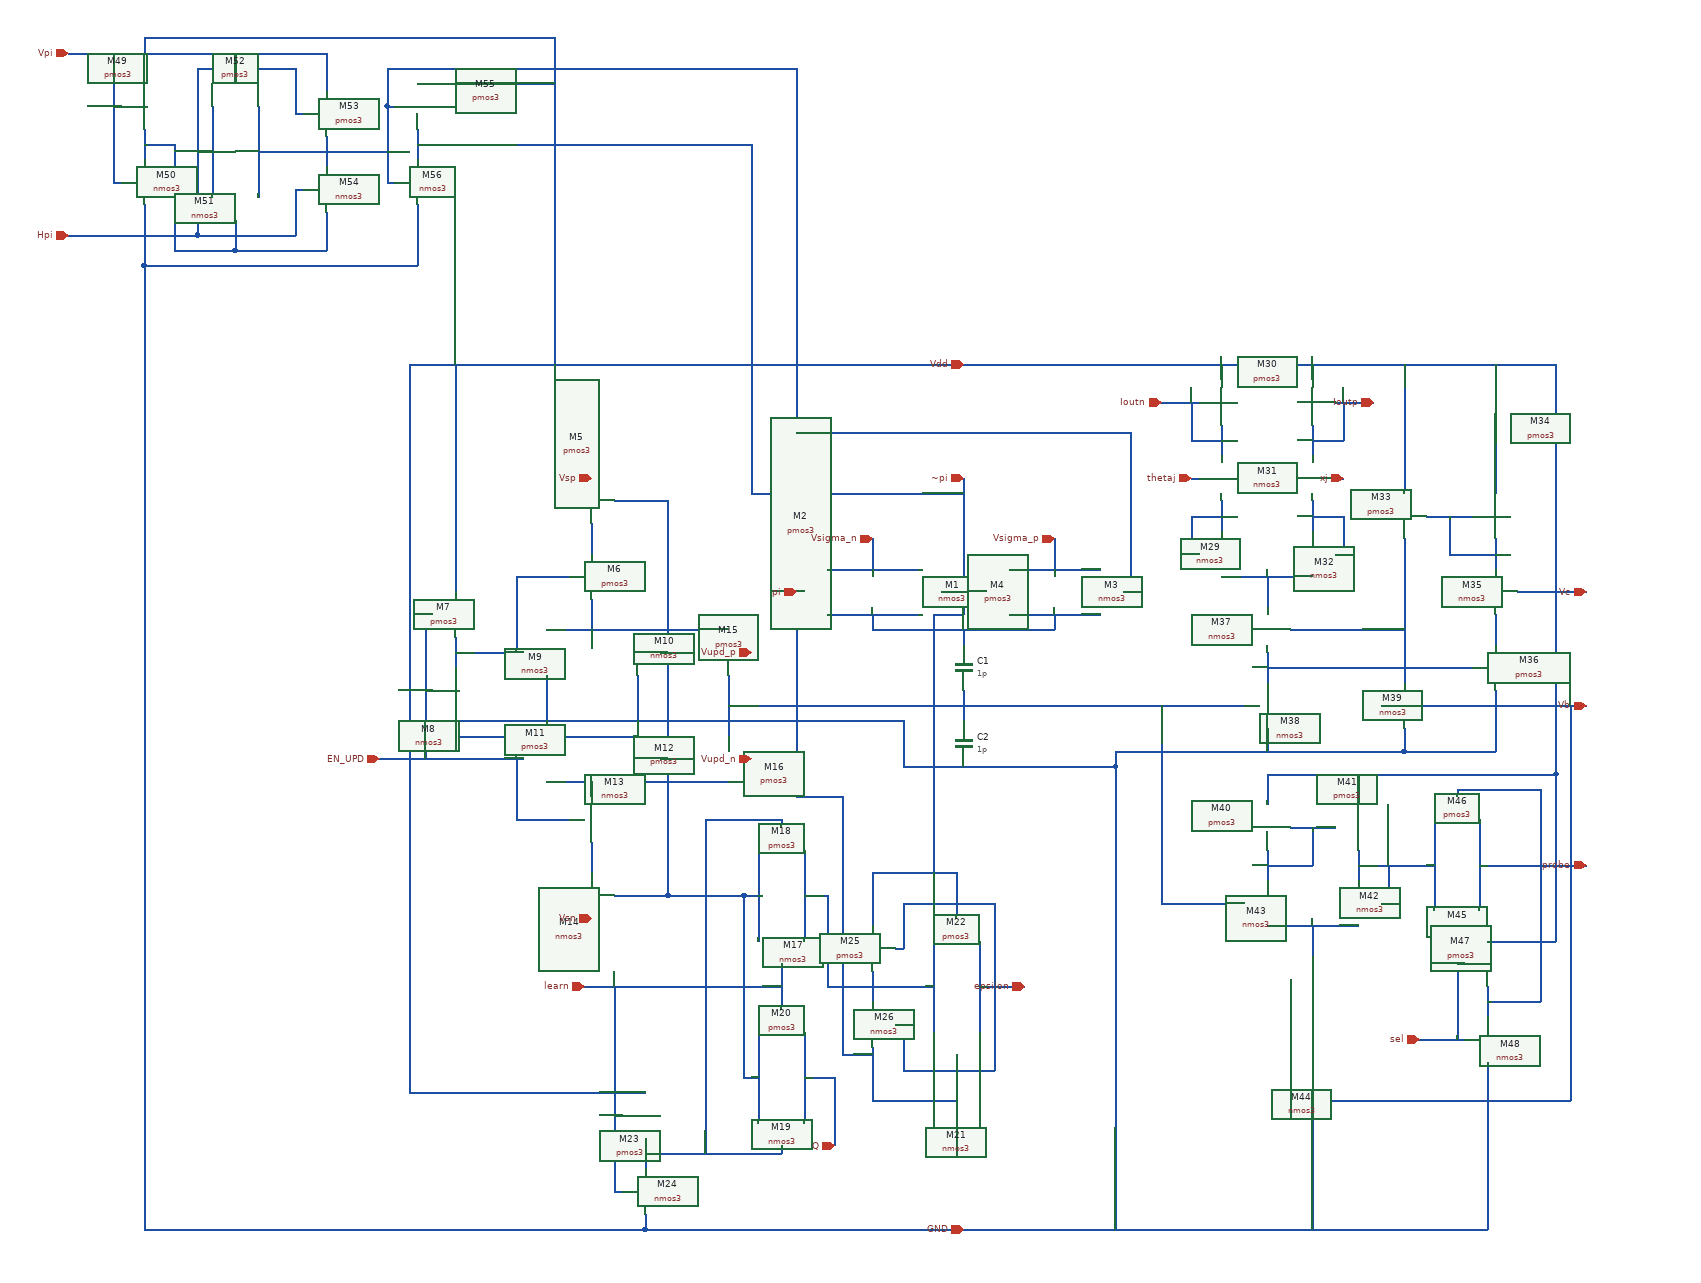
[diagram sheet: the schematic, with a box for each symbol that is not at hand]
v {xschem version=3.4.5 file_version=1.2
}
G {}
K {}
V {}
S {}
E {}
N -180 -80 -60 -80 {
lab=Vsigma_n}
N 60 -80 180 -80 {
lab=Vsigma_p}
N -180 -20 -60 -20 {
lab=#net1}
N 60 -20 180 -20 {
lab=#net1}
N -30 -50 30 -50 {
lab=~pi}
N 0 -200 0 -50 {
lab=~pi}
N -220 -50 -210 -50 {
lab=pi}
N 210 -50 220 -50 {
lab=pi}
N -120 -20 -120 0 {
lab=#net1}
N -120 0 120 0 {
lab=#net1}
N 120 -20 120 0 {
lab=#net1}
N 0 0 0 20 {
lab=#net1}
N -550 0 -430 0 {
lab=#net2}
N -490 -40 -490 0 {
lab=#net2}
N -490 -140 -490 -100 {
lab=#net3}
N -590 -70 -520 -70 {
lab=#net4}
N -590 -70 -590 30 {
lab=#net4}
N -670 10 -670 50 {
lab=#net4}
N -670 30 -580 30 {
lab=#net4}
N -490 280 -490 320 {
lab=#net5}
N -550 200 -430 200 {
lab=#net6}
N -490 200 -490 220 {
lab=#net6}
N -460 350 -390 350 {
lab=#net7}
N -400 170 -390 170 {
lab=#net7}
N -400 30 -390 30 {
lab=#net7}
N -710 -20 -700 -20 {
lab=EN_UPD}
N -710 80 -700 80 {
lab=EN_UPD}
N -590 170 -590 250 {
lab=EN_UPD}
N -590 250 -520 250 {
lab=EN_UPD}
N -460 -170 -390 -170 {
lab=#net7}
N -390 -170 -390 350 {
lab=#net7}
N -710 -20 -710 170 {
lab=EN_UPD}
N -310 60 -310 140 {
lab=#net8}
N -430 0 -310 0 {
lab=#net2}
N -430 200 -310 200 {
lab=#net6}
N -310 100 -0 100 {
lab=#net8}
N -0 80 0 120 {
lab=#net8}
N -210 290 -210 410 {
lab=#net9}
N -210 530 -210 650 {
lab=Q}
N -270 290 -270 410 {
lab=#net7}
N -270 530 -270 650 {
lab=#net7}
N -240 440 -240 500 {
lab=learn}
N -240 250 -240 260 {
lab=#net10}
N -240 680 -240 690 {
lab=#net10}
N -290 350 -270 350 {
lab=#net7}
N -290 350 -290 590 {
lab=#net7}
N -290 590 -270 590 {
lab=#net7}
N 20 410 20 530 {
lab=epsilon}
N -40 410 -40 530 {
lab=#net9}
N -420 670 -420 710 {
lab=#net10}
N -460 640 -450 640 {
lab=learn}
N -460 740 -450 740 {
lab=learn}
N -420 690 -240 690 {
lab=#net10}
N -460 470 -460 740 {
lab=learn}
N -500 470 -240 470 {
lab=learn}
N -340 250 -240 250 {
lab=#net10}
N -340 250 -340 690 {
lab=#net10}
N -390 350 -290 350 {
lab=#net7}
N -120 450 -120 490 {
lab=#net9}
N -210 350 -180 350 {
lab=#net9}
N -180 350 -180 470 {
lab=#net9}
N -180 470 -120 470 {
lab=#net9}
N -120 470 -40 470 {
lab=#net9}
N -120 550 -120 620 {
lab=pi}
N -120 620 -10 620 {
lab=pi}
N -10 560 -10 620 {
lab=pi}
N -120 320 -120 390 {
lab=~pi}
N -120 320 -10 320 {
lab=~pi}
N -10 320 -10 380 {
lab=~pi}
N -90 520 -80 520 {
lab=epsilon}
N -80 520 -80 580 {
lab=epsilon}
N -80 580 40 580 {
lab=epsilon}
N 40 360 40 580 {
lab=epsilon}
N -80 360 40 360 {
lab=epsilon}
N -80 360 -80 420 {
lab=epsilon}
N -90 420 -80 420 {
lab=epsilon}
N 20 470 40 470 {
lab=epsilon}
N 340 -270 340 -230 {
lab=Ioutn}
N 300 -200 310 -200 {
lab=thetaj}
N 460 -270 460 -230 {
lab=Ioutp}
N 490 -200 500 -200 {
lab=xj}
N 340 -170 340 -130 {
lab=#net11}
N 460 -170 460 -130 {
lab=#net12}
N 300 -100 310 -100 {
lab=#net11}
N 300 -150 300 -100 {
lab=#net11}
N 300 -150 340 -150 {
lab=#net11}
N 460 -150 500 -150 {
lab=#net12}
N 500 -150 500 -100 {
lab=#net12}
N 490 -100 500 -100 {
lab=#net12}
N 340 -70 460 -70 {
lab=#net13}
N 300 -300 300 -250 {
lab=Ioutn}
N 300 -250 340 -250 {
lab=Ioutn}
N 460 -250 500 -250 {
lab=Ioutp}
N 500 -300 500 -250 {
lab=Ioutp}
N 260 -300 310 -300 {
lab=Ioutn}
N 490 -300 540 -300 {
lab=Ioutp}
N 400 -70 400 -30 {
lab=#net13}
N 400 30 400 70 {
lab=#net14}
N 610 -150 670 -150 {
lab=#net15}
N 640 -150 640 -100 {
lab=#net15}
N 640 -100 700 -100 {
lab=#net15}
N 700 -120 700 -80 {
lab=#net15}
N 700 -20 700 20 {
lab=#net16}
N 400 50 670 50 {
lab=#net14}
N 580 -120 580 70 {
lab=#net17}
N 430 0 580 0 {
lab=#net17}
N 430 260 490 260 {
lab=#net18}
N 520 290 520 330 {
lab=#net19}
N 460 260 460 310 {
lab=#net18}
N 400 310 460 310 {
lab=#net18}
N 400 290 400 330 {
lab=#net18}
N 400 390 520 390 {
lab=#net20}
N 460 390 460 430 {
lab=#net20}
N 680 250 680 370 {
lab=probe}
N 620 250 620 370 {
lab=#net19}
N 40 470 80 470 {
lab=epsilon}
N 690 470 690 510 {
lab=#net21}
N 650 440 660 440 {
lab=sel}
N 520 310 620 310 {
lab=#net19}
N 550 360 560 360 {
lab=#net19}
N 560 310 560 360 {
lab=#net19}
N 650 400 650 540 {
lab=sel}
N 600 540 660 540 {
lab=sel}
N 650 210 650 220 {
lab=#net21}
N 650 210 760 210 {
lab=#net21}
N 690 490 760 490 {
lab=#net21}
N 760 210 760 490 {
lab=#net21}
N 0 100 370 100 {
lab=#net8}
N 260 360 370 360 {
lab=#net8}
N 260 100 260 360 {
lab=#net8}
N 460 -350 460 -330 {
lab=Vdd}
N 340 -350 340 -330 {
lab=Vdd}
N -670 -350 -670 -50 {
lab=Vdd}
N 700 -350 700 -180 {
lab=Vdd}
N 580 -350 580 -180 {
lab=Vdd}
N -730 140 -430 140 {
lab=Vdd}
N -730 -350 -730 140 {
lab=Vdd}
N 400 190 400 230 {
lab=Vdd}
N 520 190 520 230 {
lab=Vdd}
N 400 190 780 190 {
lab=Vdd}
N 780 -350 780 190 {
lab=Vdd}
N -730 -350 780 -350 {
lab=Vdd}
N 690 410 780 410 {
lab=Vdd}
N 780 190 780 410 {
lab=Vdd}
N -730 610 -420 610 {
lab=Vdd}
N -730 140 -730 610 {
lab=Vdd}
N -420 770 -420 790 {
lab=GND}
N -420 790 690 790 {
lab=GND}
N 690 570 690 790 {
lab=GND}
N 460 490 460 790 {
lab=GND}
N -0 180 200 180 {
lab=GND}
N 200 180 200 790 {
lab=GND}
N 580 130 580 160 {
lab=GND}
N 200 160 580 160 {
lab=GND}
N 200 160 200 180 {
lab=GND}
N 400 130 400 160 {
lab=GND}
N 700 80 700 160 {
lab=GND}
N 580 160 700 160 {
lab=GND}
N -670 110 -670 120 {
lab=GND}
N -670 120 -80 120 {
lab=GND}
N -80 120 -80 180 {
lab=GND}
N -80 180 -0 180 {
lab=GND}
N -550 60 -550 120 {
lab=GND}
N -430 60 -430 120 {
lab=GND}
N 730 -50 820 -50 {
lab=Vc}
N 680 310 820 310 {
lab=probe}
N -120 -120 -120 -80 {
lab=Vsigma_n}
N 120 -120 120 -80 {
lab=Vsigma_p}
N 550 100 820 100 {
lab=Vb}
N 430 460 430 620 {
lab=Vb}
N 430 620 800 620 {
lab=Vb}
N 800 100 800 620 {
lab=Vb}
N -210 590 -170 590 {
lab=Q}
N -170 590 -170 680 {
lab=Q}
N -220 -50 -220 220 {
lab=pi}
N -220 220 -160 220 {
lab=pi}
N -160 220 -160 560 {
lab=pi}
N -160 560 -120 560 {
lab=pi}
N 0 -50 0 -20 {
lab=~pi}
N -40 -20 0 -20 {
lab=~pi}
N -40 -20 -40 320 {
lab=~pi}
N -770 170 -580 170 {
lab=EN_UPD}
N -1080 -660 -1080 -620 {
lab=#net22}
N -1120 -690 -1110 -690 {
lab=Vpi}
N -1120 -590 -1110 -590 {
lab=Vpi}
N -930 -690 -930 -570 {
lab=pi}
N -990 -690 -990 -570 {
lab=Vpi}
N -840 -650 -840 -610 {
lab=pi}
N -880 -680 -870 -680 {
lab=Vpi}
N -880 -580 -870 -580 {
lab=Vpi}
N -720 -660 -720 -620 {
lab=~pi}
N -760 -690 -750 -690 {
lab=pi}
N -760 -590 -750 -590 {
lab=pi}
N -880 -740 -880 -680 {
lab=Vpi}
N -1010 -740 -880 -740 {
lab=Vpi}
N -1010 -740 -1010 -520 {
lab=Vpi}
N -1010 -520 -880 -520 {
lab=Vpi}
N -880 -580 -880 -520 {
lab=Vpi}
N -930 -630 -840 -630 {
lab=pi}
N -760 -690 -760 -590 {
lab=pi}
N -840 -630 -760 -630 {
lab=pi}
N -720 -640 -640 -640 {
lab=~pi}
N -760 -740 -760 -690 {
lab=pi}
N -760 -740 -640 -740 {
lab=pi}
N 220 -260 220 -50 {
lab=pi}
N -220 -260 220 -260 {
lab=pi}
N -960 -540 -960 -500 {
lab=#net22}
N -960 -500 -840 -500 {
lab=#net22}
N -840 -550 -840 -500 {
lab=#net22}
N -840 -760 -840 -710 {
lab=Vpi}
N -1080 -640 -1040 -640 {
lab=#net22}
N -1040 -640 -1040 -500 {
lab=#net22}
N -1040 -500 -960 -500 {
lab=#net22}
N -1180 -760 -840 -760 {
lab=Vpi}
N -1120 -760 -1120 -590 {
lab=Vpi}
N -720 -560 -720 -480 {
lab=GND}
N -1080 -480 -720 -480 {
lab=GND}
N -1080 -560 -1080 -480 {
lab=GND}
N -1080 -480 -1080 790 {
lab=GND}
N -1080 790 -420 790 {
lab=GND}
N -960 -760 -960 -720 {
lab=Vpi}
N -1080 -780 -1080 -720 {
lab=Vdd}
N -1080 -780 -540 -780 {
lab=Vdd}
N -540 -780 -540 -350 {
lab=Vdd}
N -720 -720 -540 -720 {
lab=Vdd}
N -640 -740 -220 -740 {
lab=pi}
N -220 -740 -220 -50 {
lab=pi}
N -640 -640 -280 -640 {
lab=~pi}
N -280 -640 -280 -180 {
lab=~pi}
N -280 -180 0 -180 {
lab=~pi}
N -1010 -630 -990 -630 {
lab=Vpi}
N -1180 -520 -1010 -520 {
lab=Vpi}
C {madvlsi/nmos3.sym} -60 -50 0 1 {name=M1
L=0.15
W=1
body=GND
nf=1
mult=1
ad="'int((nf+1)/2) * W/nf * 0.29'" 
pd="'2*int((nf+1)/2) * (W/nf + 0.29)'"
as="'int((nf+2)/2) * W/nf * 0.29'" 
ps="'2*int((nf+2)/2) * (W/nf + 0.29)'"
nrd="'0.29 / W'" nrs="'0.29 / W'"
sa=0 sb=0 sd=0
model=nfet_01v8
spiceprefix=X
}
C {madvlsi/pmos3.sym} -180 -50 0 0 {name=M2
L=0.15
W=1
body=VDD
nf=1
mult=1
ad="'int((nf+1)/2) * W/nf * 0.29'" 
pd="'2*int((nf+1)/2) * (W/nf + 0.29)'"
as="'int((nf+2)/2) * W/nf * 0.29'" 
ps="'2*int((nf+2)/2) * (W/nf + 0.29)'"
nrd="'0.29 / W'" nrs="'0.29 / W'"
sa=0 sb=0 sd=0
model=pfet_01v8
spiceprefix=X
}
C {madvlsi/nmos3.sym} 180 -50 0 1 {name=M3
L=0.15
W=1
body=GND
nf=1
mult=1
ad="'int((nf+1)/2) * W/nf * 0.29'" 
pd="'2*int((nf+1)/2) * (W/nf + 0.29)'"
as="'int((nf+2)/2) * W/nf * 0.29'" 
ps="'2*int((nf+2)/2) * (W/nf + 0.29)'"
nrd="'0.29 / W'" nrs="'0.29 / W'"
sa=0 sb=0 sd=0
model=nfet_01v8
spiceprefix=X
}
C {madvlsi/pmos3.sym} 60 -50 0 0 {name=M4
L=0.15
W=1
body=VDD
nf=1
mult=1
ad="'int((nf+1)/2) * W/nf * 0.29'" 
pd="'2*int((nf+1)/2) * (W/nf + 0.29)'"
as="'int((nf+2)/2) * W/nf * 0.29'" 
ps="'2*int((nf+2)/2) * (W/nf + 0.29)'"
nrd="'0.29 / W'" nrs="'0.29 / W'"
sa=0 sb=0 sd=0
model=pfet_01v8
spiceprefix=X
}
C {madvlsi/capacitor.sym} 0 50 0 0 {name=C1
value=1p
m=1}
C {madvlsi/capacitor.sym} 0 150 0 0 {name=C2
value=1p
m=1}
C {madvlsi/pmos3.sym} -490 -170 0 1 {name=M5
L=0.15
W=1
body=VDD
nf=1
mult=1
ad="'int((nf+1)/2) * W/nf * 0.29'" 
pd="'2*int((nf+1)/2) * (W/nf + 0.29)'"
as="'int((nf+2)/2) * W/nf * 0.29'" 
ps="'2*int((nf+2)/2) * (W/nf + 0.29)'"
nrd="'0.29 / W'" nrs="'0.29 / W'"
sa=0 sb=0 sd=0
model=pfet_01v8
spiceprefix=X
}
C {madvlsi/pmos3.sym} -490 -70 0 0 {name=M6
L=0.15
W=1
body=VDD
nf=1
mult=1
ad="'int((nf+1)/2) * W/nf * 0.29'" 
pd="'2*int((nf+1)/2) * (W/nf + 0.29)'"
as="'int((nf+2)/2) * W/nf * 0.29'" 
ps="'2*int((nf+2)/2) * (W/nf + 0.29)'"
nrd="'0.29 / W'" nrs="'0.29 / W'"
sa=0 sb=0 sd=0
model=pfet_01v8
spiceprefix=X
}
C {madvlsi/pmos3.sym} -670 -20 0 0 {name=M7
L=0.15
W=1
body=VDD
nf=1
mult=1
ad="'int((nf+1)/2) * W/nf * 0.29'" 
pd="'2*int((nf+1)/2) * (W/nf + 0.29)'"
as="'int((nf+2)/2) * W/nf * 0.29'" 
ps="'2*int((nf+2)/2) * (W/nf + 0.29)'"
nrd="'0.29 / W'" nrs="'0.29 / W'"
sa=0 sb=0 sd=0
model=pfet_01v8
spiceprefix=X
}
C {madvlsi/nmos3.sym} -670 80 0 0 {name=M8
L=0.15
W=1
body=GND
nf=1
mult=1
ad="'int((nf+1)/2) * W/nf * 0.29'" 
pd="'2*int((nf+1)/2) * (W/nf + 0.29)'"
as="'int((nf+2)/2) * W/nf * 0.29'" 
ps="'2*int((nf+2)/2) * (W/nf + 0.29)'"
nrd="'0.29 / W'" nrs="'0.29 / W'"
sa=0 sb=0 sd=0
model=nfet_01v8
spiceprefix=X
}
C {madvlsi/nmos3.sym} -550 30 0 0 {name=M9
L=0.15
W=1
body=GND
nf=1
mult=1
ad="'int((nf+1)/2) * W/nf * 0.29'" 
pd="'2*int((nf+1)/2) * (W/nf + 0.29)'"
as="'int((nf+2)/2) * W/nf * 0.29'" 
ps="'2*int((nf+2)/2) * (W/nf + 0.29)'"
nrd="'0.29 / W'" nrs="'0.29 / W'"
sa=0 sb=0 sd=0
model=nfet_01v8
spiceprefix=X
}
C {madvlsi/nmos3.sym} -430 30 0 1 {name=M10
L=0.15
W=1
body=GND
nf=1
mult=1
ad="'int((nf+1)/2) * W/nf * 0.29'" 
pd="'2*int((nf+1)/2) * (W/nf + 0.29)'"
as="'int((nf+2)/2) * W/nf * 0.29'" 
ps="'2*int((nf+2)/2) * (W/nf + 0.29)'"
nrd="'0.29 / W'" nrs="'0.29 / W'"
sa=0 sb=0 sd=0
model=nfet_01v8
spiceprefix=X
}
C {madvlsi/pmos3.sym} -550 170 0 0 {name=M11
L=0.15
W=1
body=VDD
nf=1
mult=1
ad="'int((nf+1)/2) * W/nf * 0.29'" 
pd="'2*int((nf+1)/2) * (W/nf + 0.29)'"
as="'int((nf+2)/2) * W/nf * 0.29'" 
ps="'2*int((nf+2)/2) * (W/nf + 0.29)'"
nrd="'0.29 / W'" nrs="'0.29 / W'"
sa=0 sb=0 sd=0
model=pfet_01v8
spiceprefix=X
}
C {madvlsi/pmos3.sym} -430 170 0 1 {name=M12
L=0.15
W=1
body=VDD
nf=1
mult=1
ad="'int((nf+1)/2) * W/nf * 0.29'" 
pd="'2*int((nf+1)/2) * (W/nf + 0.29)'"
as="'int((nf+2)/2) * W/nf * 0.29'" 
ps="'2*int((nf+2)/2) * (W/nf + 0.29)'"
nrd="'0.29 / W'" nrs="'0.29 / W'"
sa=0 sb=0 sd=0
model=pfet_01v8
spiceprefix=X
}
C {madvlsi/nmos3.sym} -490 250 0 0 {name=M13
L=0.15
W=1
body=GND
nf=1
mult=1
ad="'int((nf+1)/2) * W/nf * 0.29'" 
pd="'2*int((nf+1)/2) * (W/nf + 0.29)'"
as="'int((nf+2)/2) * W/nf * 0.29'" 
ps="'2*int((nf+2)/2) * (W/nf + 0.29)'"
nrd="'0.29 / W'" nrs="'0.29 / W'"
sa=0 sb=0 sd=0
model=nfet_01v8
spiceprefix=X
}
C {madvlsi/nmos3.sym} -490 350 0 1 {name=M14
L=0.15
W=1
body=GND
nf=1
mult=1
ad="'int((nf+1)/2) * W/nf * 0.29'" 
pd="'2*int((nf+1)/2) * (W/nf + 0.29)'"
as="'int((nf+2)/2) * W/nf * 0.29'" 
ps="'2*int((nf+2)/2) * (W/nf + 0.29)'"
nrd="'0.29 / W'" nrs="'0.29 / W'"
sa=0 sb=0 sd=0
model=nfet_01v8
spiceprefix=X
}
C {madvlsi/pmos3.sym} -310 30 0 1 {name=M15
L=0.15
W=1
body=VDD
nf=1
mult=1
ad="'int((nf+1)/2) * W/nf * 0.29'" 
pd="'2*int((nf+1)/2) * (W/nf + 0.29)'"
as="'int((nf+2)/2) * W/nf * 0.29'" 
ps="'2*int((nf+2)/2) * (W/nf + 0.29)'"
nrd="'0.29 / W'" nrs="'0.29 / W'"
sa=0 sb=0 sd=0
model=pfet_01v8
spiceprefix=X
}
C {madvlsi/pmos3.sym} -310 170 0 1 {name=M16
L=0.15
W=1
body=VDD
nf=1
mult=1
ad="'int((nf+1)/2) * W/nf * 0.29'" 
pd="'2*int((nf+1)/2) * (W/nf + 0.29)'"
as="'int((nf+2)/2) * W/nf * 0.29'" 
ps="'2*int((nf+2)/2) * (W/nf + 0.29)'"
nrd="'0.29 / W'" nrs="'0.29 / W'"
sa=0 sb=0 sd=0
model=pfet_01v8
spiceprefix=X
}
C {madvlsi/nmos3.sym} -240 410 1 1 {name=M17
L=0.15
W=1
body=GND
nf=1
mult=1
ad="'int((nf+1)/2) * W/nf * 0.29'" 
pd="'2*int((nf+1)/2) * (W/nf + 0.29)'"
as="'int((nf+2)/2) * W/nf * 0.29'" 
ps="'2*int((nf+2)/2) * (W/nf + 0.29)'"
nrd="'0.29 / W'" nrs="'0.29 / W'"
sa=0 sb=0 sd=0
model=nfet_01v8
spiceprefix=X
}
C {madvlsi/pmos3.sym} -240 290 1 0 {name=M18
L=0.15
W=1
body=VDD
nf=1
mult=1
ad="'int((nf+1)/2) * W/nf * 0.29'" 
pd="'2*int((nf+1)/2) * (W/nf + 0.29)'"
as="'int((nf+2)/2) * W/nf * 0.29'" 
ps="'2*int((nf+2)/2) * (W/nf + 0.29)'"
nrd="'0.29 / W'" nrs="'0.29 / W'"
sa=0 sb=0 sd=0
model=pfet_01v8
spiceprefix=X
}
C {madvlsi/nmos3.sym} -240 650 1 1 {name=M19
L=0.15
W=1
body=GND
nf=1
mult=1
ad="'int((nf+1)/2) * W/nf * 0.29'" 
pd="'2*int((nf+1)/2) * (W/nf + 0.29)'"
as="'int((nf+2)/2) * W/nf * 0.29'" 
ps="'2*int((nf+2)/2) * (W/nf + 0.29)'"
nrd="'0.29 / W'" nrs="'0.29 / W'"
sa=0 sb=0 sd=0
model=nfet_01v8
spiceprefix=X
}
C {madvlsi/pmos3.sym} -240 530 1 0 {name=M20
L=0.15
W=1
body=VDD
nf=1
mult=1
ad="'int((nf+1)/2) * W/nf * 0.29'" 
pd="'2*int((nf+1)/2) * (W/nf + 0.29)'"
as="'int((nf+2)/2) * W/nf * 0.29'" 
ps="'2*int((nf+2)/2) * (W/nf + 0.29)'"
nrd="'0.29 / W'" nrs="'0.29 / W'"
sa=0 sb=0 sd=0
model=pfet_01v8
spiceprefix=X
}
C {madvlsi/nmos3.sym} -10 530 1 1 {name=M21
L=0.15
W=1
body=GND
nf=1
mult=1
ad="'int((nf+1)/2) * W/nf * 0.29'" 
pd="'2*int((nf+1)/2) * (W/nf + 0.29)'"
as="'int((nf+2)/2) * W/nf * 0.29'" 
ps="'2*int((nf+2)/2) * (W/nf + 0.29)'"
nrd="'0.29 / W'" nrs="'0.29 / W'"
sa=0 sb=0 sd=0
model=nfet_01v8
spiceprefix=X
}
C {madvlsi/pmos3.sym} -10 410 1 0 {name=M22
L=0.15
W=1
body=VDD
nf=1
mult=1
ad="'int((nf+1)/2) * W/nf * 0.29'" 
pd="'2*int((nf+1)/2) * (W/nf + 0.29)'"
as="'int((nf+2)/2) * W/nf * 0.29'" 
ps="'2*int((nf+2)/2) * (W/nf + 0.29)'"
nrd="'0.29 / W'" nrs="'0.29 / W'"
sa=0 sb=0 sd=0
model=pfet_01v8
spiceprefix=X
}
C {madvlsi/pmos3.sym} -420 640 0 0 {name=M23
L=0.15
W=1
body=VDD
nf=1
mult=1
ad="'int((nf+1)/2) * W/nf * 0.29'" 
pd="'2*int((nf+1)/2) * (W/nf + 0.29)'"
as="'int((nf+2)/2) * W/nf * 0.29'" 
ps="'2*int((nf+2)/2) * (W/nf + 0.29)'"
nrd="'0.29 / W'" nrs="'0.29 / W'"
sa=0 sb=0 sd=0
model=pfet_01v8
spiceprefix=X
}
C {madvlsi/nmos3.sym} -420 740 0 0 {name=M24
L=0.15
W=1
body=GND
nf=1
mult=1
ad="'int((nf+1)/2) * W/nf * 0.29'" 
pd="'2*int((nf+1)/2) * (W/nf + 0.29)'"
as="'int((nf+2)/2) * W/nf * 0.29'" 
ps="'2*int((nf+2)/2) * (W/nf + 0.29)'"
nrd="'0.29 / W'" nrs="'0.29 / W'"
sa=0 sb=0 sd=0
model=nfet_01v8
spiceprefix=X
}
C {madvlsi/pmos3.sym} -120 420 0 1 {name=M25
L=0.15
W=1
body=VDD
nf=1
mult=1
ad="'int((nf+1)/2) * W/nf * 0.29'" 
pd="'2*int((nf+1)/2) * (W/nf + 0.29)'"
as="'int((nf+2)/2) * W/nf * 0.29'" 
ps="'2*int((nf+2)/2) * (W/nf + 0.29)'"
nrd="'0.29 / W'" nrs="'0.29 / W'"
sa=0 sb=0 sd=0
model=pfet_01v8
spiceprefix=X
}
C {madvlsi/nmos3.sym} -120 520 0 1 {name=M26
L=0.15
W=1
body=GND
nf=1
mult=1
ad="'int((nf+1)/2) * W/nf * 0.29'" 
pd="'2*int((nf+1)/2) * (W/nf + 0.29)'"
as="'int((nf+2)/2) * W/nf * 0.29'" 
ps="'2*int((nf+2)/2) * (W/nf + 0.29)'"
nrd="'0.29 / W'" nrs="'0.29 / W'"
sa=0 sb=0 sd=0
model=nfet_01v8
spiceprefix=X
}
C {madvlsi/pmos3.sym} 340 -300 0 0 {name=M27
L=0.15
W=1
body=VDD
nf=1
mult=1
ad="'int((nf+1)/2) * W/nf * 0.29'" 
pd="'2*int((nf+1)/2) * (W/nf + 0.29)'"
as="'int((nf+2)/2) * W/nf * 0.29'" 
ps="'2*int((nf+2)/2) * (W/nf + 0.29)'"
nrd="'0.29 / W'" nrs="'0.29 / W'"
sa=0 sb=0 sd=0
model=pfet_01v8
spiceprefix=X
}
C {madvlsi/nmos3.sym} 340 -200 0 0 {name=M28
L=0.15
W=1
body=GND
nf=1
mult=1
ad="'int((nf+1)/2) * W/nf * 0.29'" 
pd="'2*int((nf+1)/2) * (W/nf + 0.29)'"
as="'int((nf+2)/2) * W/nf * 0.29'" 
ps="'2*int((nf+2)/2) * (W/nf + 0.29)'"
nrd="'0.29 / W'" nrs="'0.29 / W'"
sa=0 sb=0 sd=0
model=nfet_01v8
spiceprefix=X
}
C {madvlsi/nmos3.sym} 340 -100 0 0 {name=M29
L=0.15
W=1
body=GND
nf=1
mult=1
ad="'int((nf+1)/2) * W/nf * 0.29'" 
pd="'2*int((nf+1)/2) * (W/nf + 0.29)'"
as="'int((nf+2)/2) * W/nf * 0.29'" 
ps="'2*int((nf+2)/2) * (W/nf + 0.29)'"
nrd="'0.29 / W'" nrs="'0.29 / W'"
sa=0 sb=0 sd=0
model=nfet_01v8
spiceprefix=X
}
C {madvlsi/pmos3.sym} 460 -300 0 1 {name=M30
L=0.15
W=1
body=VDD
nf=1
mult=1
ad="'int((nf+1)/2) * W/nf * 0.29'" 
pd="'2*int((nf+1)/2) * (W/nf + 0.29)'"
as="'int((nf+2)/2) * W/nf * 0.29'" 
ps="'2*int((nf+2)/2) * (W/nf + 0.29)'"
nrd="'0.29 / W'" nrs="'0.29 / W'"
sa=0 sb=0 sd=0
model=pfet_01v8
spiceprefix=X
}
C {madvlsi/nmos3.sym} 460 -200 0 1 {name=M31
L=0.15
W=1
body=GND
nf=1
mult=1
ad="'int((nf+1)/2) * W/nf * 0.29'" 
pd="'2*int((nf+1)/2) * (W/nf + 0.29)'"
as="'int((nf+2)/2) * W/nf * 0.29'" 
ps="'2*int((nf+2)/2) * (W/nf + 0.29)'"
nrd="'0.29 / W'" nrs="'0.29 / W'"
sa=0 sb=0 sd=0
model=nfet_01v8
spiceprefix=X
}
C {madvlsi/nmos3.sym} 460 -100 0 1 {name=M32
L=0.15
W=1
body=GND
nf=1
mult=1
ad="'int((nf+1)/2) * W/nf * 0.29'" 
pd="'2*int((nf+1)/2) * (W/nf + 0.29)'"
as="'int((nf+2)/2) * W/nf * 0.29'" 
ps="'2*int((nf+2)/2) * (W/nf + 0.29)'"
nrd="'0.29 / W'" nrs="'0.29 / W'"
sa=0 sb=0 sd=0
model=nfet_01v8
spiceprefix=X
}
C {madvlsi/pmos3.sym} 580 -150 0 1 {name=M33
L=0.15
W=1
body=VDD
nf=1
mult=1
ad="'int((nf+1)/2) * W/nf * 0.29'" 
pd="'2*int((nf+1)/2) * (W/nf + 0.29)'"
as="'int((nf+2)/2) * W/nf * 0.29'" 
ps="'2*int((nf+2)/2) * (W/nf + 0.29)'"
nrd="'0.29 / W'" nrs="'0.29 / W'"
sa=0 sb=0 sd=0
model=pfet_01v8
spiceprefix=X
}
C {madvlsi/pmos3.sym} 700 -150 0 0 {name=M34
L=0.15
W=1
body=VDD
nf=1
mult=1
ad="'int((nf+1)/2) * W/nf * 0.29'" 
pd="'2*int((nf+1)/2) * (W/nf + 0.29)'"
as="'int((nf+2)/2) * W/nf * 0.29'" 
ps="'2*int((nf+2)/2) * (W/nf + 0.29)'"
nrd="'0.29 / W'" nrs="'0.29 / W'"
sa=0 sb=0 sd=0
model=pfet_01v8
spiceprefix=X
}
C {madvlsi/nmos3.sym} 700 -50 0 1 {name=M35
L=0.15
W=1
body=GND
nf=1
mult=1
ad="'int((nf+1)/2) * W/nf * 0.29'" 
pd="'2*int((nf+1)/2) * (W/nf + 0.29)'"
as="'int((nf+2)/2) * W/nf * 0.29'" 
ps="'2*int((nf+2)/2) * (W/nf + 0.29)'"
nrd="'0.29 / W'" nrs="'0.29 / W'"
sa=0 sb=0 sd=0
model=nfet_01v8
spiceprefix=X
}
C {madvlsi/pmos3.sym} 700 50 0 0 {name=M36
L=0.15
W=1
body=VDD
nf=1
mult=1
ad="'int((nf+1)/2) * W/nf * 0.29'" 
pd="'2*int((nf+1)/2) * (W/nf + 0.29)'"
as="'int((nf+2)/2) * W/nf * 0.29'" 
ps="'2*int((nf+2)/2) * (W/nf + 0.29)'"
nrd="'0.29 / W'" nrs="'0.29 / W'"
sa=0 sb=0 sd=0
model=pfet_01v8
spiceprefix=X
}
C {madvlsi/nmos3.sym} 400 0 0 1 {name=M37
L=0.15
W=1
body=GND
nf=1
mult=1
ad="'int((nf+1)/2) * W/nf * 0.29'" 
pd="'2*int((nf+1)/2) * (W/nf + 0.29)'"
as="'int((nf+2)/2) * W/nf * 0.29'" 
ps="'2*int((nf+2)/2) * (W/nf + 0.29)'"
nrd="'0.29 / W'" nrs="'0.29 / W'"
sa=0 sb=0 sd=0
model=nfet_01v8
spiceprefix=X
}
C {madvlsi/nmos3.sym} 400 100 0 0 {name=M38
L=0.15
W=1
body=GND
nf=1
mult=1
ad="'int((nf+1)/2) * W/nf * 0.29'" 
pd="'2*int((nf+1)/2) * (W/nf + 0.29)'"
as="'int((nf+2)/2) * W/nf * 0.29'" 
ps="'2*int((nf+2)/2) * (W/nf + 0.29)'"
nrd="'0.29 / W'" nrs="'0.29 / W'"
sa=0 sb=0 sd=0
model=nfet_01v8
spiceprefix=X
}
C {madvlsi/nmos3.sym} 580 100 0 0 {name=M39
L=0.15
W=1
body=GND
nf=1
mult=1
ad="'int((nf+1)/2) * W/nf * 0.29'" 
pd="'2*int((nf+1)/2) * (W/nf + 0.29)'"
as="'int((nf+2)/2) * W/nf * 0.29'" 
ps="'2*int((nf+2)/2) * (W/nf + 0.29)'"
nrd="'0.29 / W'" nrs="'0.29 / W'"
sa=0 sb=0 sd=0
model=nfet_01v8
spiceprefix=X
}
C {madvlsi/pmos3.sym} 400 260 0 1 {name=M40
L=0.15
W=1
body=VDD
nf=1
mult=1
ad="'int((nf+1)/2) * W/nf * 0.29'" 
pd="'2*int((nf+1)/2) * (W/nf + 0.29)'"
as="'int((nf+2)/2) * W/nf * 0.29'" 
ps="'2*int((nf+2)/2) * (W/nf + 0.29)'"
nrd="'0.29 / W'" nrs="'0.29 / W'"
sa=0 sb=0 sd=0
model=pfet_01v8
spiceprefix=X
}
C {madvlsi/pmos3.sym} 520 260 0 0 {name=M41
L=0.15
W=1
body=VDD
nf=1
mult=1
ad="'int((nf+1)/2) * W/nf * 0.29'" 
pd="'2*int((nf+1)/2) * (W/nf + 0.29)'"
as="'int((nf+2)/2) * W/nf * 0.29'" 
ps="'2*int((nf+2)/2) * (W/nf + 0.29)'"
nrd="'0.29 / W'" nrs="'0.29 / W'"
sa=0 sb=0 sd=0
model=pfet_01v8
spiceprefix=X
}
C {madvlsi/nmos3.sym} 520 360 0 1 {name=M42
L=0.15
W=1
body=GND
nf=1
mult=1
ad="'int((nf+1)/2) * W/nf * 0.29'" 
pd="'2*int((nf+1)/2) * (W/nf + 0.29)'"
as="'int((nf+2)/2) * W/nf * 0.29'" 
ps="'2*int((nf+2)/2) * (W/nf + 0.29)'"
nrd="'0.29 / W'" nrs="'0.29 / W'"
sa=0 sb=0 sd=0
model=nfet_01v8
spiceprefix=X
}
C {madvlsi/nmos3.sym} 400 360 0 0 {name=M43
L=0.15
W=1
body=GND
nf=1
mult=1
ad="'int((nf+1)/2) * W/nf * 0.29'" 
pd="'2*int((nf+1)/2) * (W/nf + 0.29)'"
as="'int((nf+2)/2) * W/nf * 0.29'" 
ps="'2*int((nf+2)/2) * (W/nf + 0.29)'"
nrd="'0.29 / W'" nrs="'0.29 / W'"
sa=0 sb=0 sd=0
model=nfet_01v8
spiceprefix=X
}
C {madvlsi/nmos3.sym} 460 460 0 0 {name=M44
L=0.15
W=1
body=GND
nf=1
mult=1
ad="'int((nf+1)/2) * W/nf * 0.29'" 
pd="'2*int((nf+1)/2) * (W/nf + 0.29)'"
as="'int((nf+2)/2) * W/nf * 0.29'" 
ps="'2*int((nf+2)/2) * (W/nf + 0.29)'"
nrd="'0.29 / W'" nrs="'0.29 / W'"
sa=0 sb=0 sd=0
model=nfet_01v8
spiceprefix=X
}
C {madvlsi/nmos3.sym} 650 370 1 1 {name=M45
L=0.15
W=1
body=GND
nf=1
mult=1
ad="'int((nf+1)/2) * W/nf * 0.29'" 
pd="'2*int((nf+1)/2) * (W/nf + 0.29)'"
as="'int((nf+2)/2) * W/nf * 0.29'" 
ps="'2*int((nf+2)/2) * (W/nf + 0.29)'"
nrd="'0.29 / W'" nrs="'0.29 / W'"
sa=0 sb=0 sd=0
model=nfet_01v8
spiceprefix=X
}
C {madvlsi/pmos3.sym} 650 250 1 0 {name=M46
L=0.15
W=1
body=VDD
nf=1
mult=1
ad="'int((nf+1)/2) * W/nf * 0.29'" 
pd="'2*int((nf+1)/2) * (W/nf + 0.29)'"
as="'int((nf+2)/2) * W/nf * 0.29'" 
ps="'2*int((nf+2)/2) * (W/nf + 0.29)'"
nrd="'0.29 / W'" nrs="'0.29 / W'"
sa=0 sb=0 sd=0
model=pfet_01v8
spiceprefix=X
}
C {madvlsi/pmos3.sym} 690 440 0 0 {name=M47
L=0.15
W=1
body=VDD
nf=1
mult=1
ad="'int((nf+1)/2) * W/nf * 0.29'" 
pd="'2*int((nf+1)/2) * (W/nf + 0.29)'"
as="'int((nf+2)/2) * W/nf * 0.29'" 
ps="'2*int((nf+2)/2) * (W/nf + 0.29)'"
nrd="'0.29 / W'" nrs="'0.29 / W'"
sa=0 sb=0 sd=0
model=pfet_01v8
spiceprefix=X
}
C {madvlsi/nmos3.sym} 690 540 0 0 {name=M48
L=0.15
W=1
body=GND
nf=1
mult=1
ad="'int((nf+1)/2) * W/nf * 0.29'" 
pd="'2*int((nf+1)/2) * (W/nf + 0.29)'"
as="'int((nf+2)/2) * W/nf * 0.29'" 
ps="'2*int((nf+2)/2) * (W/nf + 0.29)'"
nrd="'0.29 / W'" nrs="'0.29 / W'"
sa=0 sb=0 sd=0
model=nfet_01v8
spiceprefix=X
}
C {devices/iopin.sym} 0 -350 3 0 {name=p1 lab=Vdd}
C {devices/iopin.sym} 0 790 1 0 {name=p2 lab=GND}
C {devices/iopin.sym} -490 -200 3 0 {name=p3 lab=Vsp}
C {devices/iopin.sym} 820 -50 0 0 {name=p4 lab=Vc}
C {devices/iopin.sym} -220 -50 2 0 {name=p5 lab=pi}
C {devices/iopin.sym} 0 -200 3 0 {name=p7 lab=~pi}
C {devices/iopin.sym} -120 -120 3 0 {name=p8 lab=Vsigma_n}
C {devices/iopin.sym} 120 -120 3 0 {name=p9 lab=Vsigma_p}
C {devices/iopin.sym} 260 -300 2 0 {name=p10 lab=Ioutn}
C {devices/iopin.sym} 540 -300 0 0 {name=p11 lab=Ioutp}
C {devices/iopin.sym} 300 -200 2 0 {name=p12 lab=thetaj}
C {devices/iopin.sym} 500 -200 0 0 {name=p13 lab=xj}
C {devices/iopin.sym} 820 100 0 0 {name=p14 lab=Vb}
C {devices/iopin.sym} 820 310 0 0 {name=p15 lab=probe}
C {devices/iopin.sym} 600 540 2 0 {name=p16 lab=sel}
C {devices/iopin.sym} -170 680 1 0 {name=p17 lab=Q}
C {devices/iopin.sym} 80 470 0 0 {name=p18 lab=epsilon}
C {devices/iopin.sym} -500 470 2 0 {name=p19 lab=learn}
C {devices/iopin.sym} -490 380 1 0 {name=p20 lab=Vsn}
C {devices/iopin.sym} -770 170 2 0 {name=p21 lab=EN_UPD}
C {devices/iopin.sym} -280 170 0 0 {name=p22 lab=Vupd_n}
C {devices/iopin.sym} -280 30 0 0 {name=p23 lab=Vupd_p}
C {madvlsi/pmos3.sym} -1080 -690 0 0 {name=M49
L=0.15
W=1
body=VDD
nf=1
mult=1
ad="'int((nf+1)/2) * W/nf * 0.29'" 
pd="'2*int((nf+1)/2) * (W/nf + 0.29)'"
as="'int((nf+2)/2) * W/nf * 0.29'" 
ps="'2*int((nf+2)/2) * (W/nf + 0.29)'"
nrd="'0.29 / W'" nrs="'0.29 / W'"
sa=0 sb=0 sd=0
model=pfet_01v8
spiceprefix=X
}
C {madvlsi/nmos3.sym} -1080 -590 0 0 {name=M50
L=0.15
W=1
body=GND
nf=1
mult=1
ad="'int((nf+1)/2) * W/nf * 0.29'" 
pd="'2*int((nf+1)/2) * (W/nf + 0.29)'"
as="'int((nf+2)/2) * W/nf * 0.29'" 
ps="'2*int((nf+2)/2) * (W/nf + 0.29)'"
nrd="'0.29 / W'" nrs="'0.29 / W'"
sa=0 sb=0 sd=0
model=nfet_01v8
spiceprefix=X
}
C {madvlsi/nmos3.sym} -960 -570 1 1 {name=M51
L=0.15
W=1
body=GND
nf=1
mult=1
ad="'int((nf+1)/2) * W/nf * 0.29'" 
pd="'2*int((nf+1)/2) * (W/nf + 0.29)'"
as="'int((nf+2)/2) * W/nf * 0.29'" 
ps="'2*int((nf+2)/2) * (W/nf + 0.29)'"
nrd="'0.29 / W'" nrs="'0.29 / W'"
sa=0 sb=0 sd=0
model=nfet_01v8
spiceprefix=X
}
C {madvlsi/pmos3.sym} -960 -690 1 0 {name=M52
L=0.15
W=1
body=VDD
nf=1
mult=1
ad="'int((nf+1)/2) * W/nf * 0.29'" 
pd="'2*int((nf+1)/2) * (W/nf + 0.29)'"
as="'int((nf+2)/2) * W/nf * 0.29'" 
ps="'2*int((nf+2)/2) * (W/nf + 0.29)'"
nrd="'0.29 / W'" nrs="'0.29 / W'"
sa=0 sb=0 sd=0
model=pfet_01v8
spiceprefix=X
}
C {madvlsi/pmos3.sym} -840 -680 0 0 {name=M53
L=0.15
W=1
body=VDD
nf=1
mult=1
ad="'int((nf+1)/2) * W/nf * 0.29'" 
pd="'2*int((nf+1)/2) * (W/nf + 0.29)'"
as="'int((nf+2)/2) * W/nf * 0.29'" 
ps="'2*int((nf+2)/2) * (W/nf + 0.29)'"
nrd="'0.29 / W'" nrs="'0.29 / W'"
sa=0 sb=0 sd=0
model=pfet_01v8
spiceprefix=X
}
C {madvlsi/nmos3.sym} -840 -580 0 0 {name=M54
L=0.15
W=1
body=GND
nf=1
mult=1
ad="'int((nf+1)/2) * W/nf * 0.29'" 
pd="'2*int((nf+1)/2) * (W/nf + 0.29)'"
as="'int((nf+2)/2) * W/nf * 0.29'" 
ps="'2*int((nf+2)/2) * (W/nf + 0.29)'"
nrd="'0.29 / W'" nrs="'0.29 / W'"
sa=0 sb=0 sd=0
model=nfet_01v8
spiceprefix=X
}
C {madvlsi/pmos3.sym} -720 -690 0 0 {name=M55
L=0.15
W=1
body=VDD
nf=1
mult=1
ad="'int((nf+1)/2) * W/nf * 0.29'" 
pd="'2*int((nf+1)/2) * (W/nf + 0.29)'"
as="'int((nf+2)/2) * W/nf * 0.29'" 
ps="'2*int((nf+2)/2) * (W/nf + 0.29)'"
nrd="'0.29 / W'" nrs="'0.29 / W'"
sa=0 sb=0 sd=0
model=pfet_01v8
spiceprefix=X
}
C {madvlsi/nmos3.sym} -720 -590 0 0 {name=M56
L=0.15
W=1
body=GND
nf=1
mult=1
ad="'int((nf+1)/2) * W/nf * 0.29'" 
pd="'2*int((nf+1)/2) * (W/nf + 0.29)'"
as="'int((nf+2)/2) * W/nf * 0.29'" 
ps="'2*int((nf+2)/2) * (W/nf + 0.29)'"
nrd="'0.29 / W'" nrs="'0.29 / W'"
sa=0 sb=0 sd=0
model=nfet_01v8
spiceprefix=X
}
C {devices/iopin.sym} -1180 -760 2 0 {name=p6 lab=Vpi}
C {devices/iopin.sym} -1180 -520 2 0 {name=p24 lab=Hpi}
